VERSION 5.7 ;
  NOWIREEXTENSIONATPIN ON ;
  DIVIDERCHAR "/" ;
  BUSBITCHARS "[]" ;
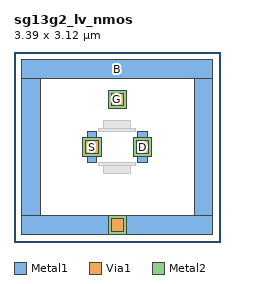
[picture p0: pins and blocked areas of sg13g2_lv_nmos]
MACRO sg13g2_lv_nmos
  CLASS BLOCK ;
  FOREIGN sg13g2_lv_nmos ;
  ORIGIN 1.130 1.310 ;
  SIZE 3.390 BY 3.120 ;
  PIN S
    ANTENNADIFFAREA 0.132500 ;
    PORT
      LAYER Metal1 ;
        RECT 0.070 0.400 0.230 0.500 ;
        RECT 0.000 0.100 0.300 0.400 ;
        RECT 0.070 0.000 0.230 0.100 ;
      LAYER Via1 ;
        RECT 0.050 0.150 0.250 0.350 ;
      LAYER Metal2 ;
        RECT 0.000 0.100 0.300 0.400 ;
    END
  END S
  PIN D
    ANTENNADIFFAREA 0.132500 ;
    PORT
      LAYER Metal1 ;
        RECT 0.900 0.400 1.060 0.500 ;
        RECT 0.830 0.100 1.130 0.400 ;
        RECT 0.900 0.000 1.060 0.100 ;
      LAYER Via1 ;
        RECT 0.880 0.150 1.080 0.350 ;
      LAYER Metal2 ;
        RECT 0.830 0.100 1.130 0.400 ;
    END
  END D
  PIN G
    PORT
      LAYER Metal1 ;
        RECT 0.415 0.880 0.715 1.180 ;
      LAYER Via1 ;
        RECT 0.465 0.930 0.665 1.130 ;
      LAYER Metal2 ;
        RECT 0.415 0.880 0.715 1.180 ;
    END
  END G
  PIN B
    ANTENNADIFFAREA 3.234000 ;
    PORT
      LAYER Metal1 ;
        RECT -1.000 1.380 2.130 1.680 ;
        RECT -1.000 -0.880 -0.700 1.380 ;
        RECT 1.830 -0.880 2.130 1.380 ;
        RECT -1.000 -1.180 2.130 -0.880 ;
      LAYER Via1 ;
        RECT 0.465 -1.130 0.665 -0.930 ;
      LAYER Metal2 ;
        RECT 0.415 -1.180 0.715 -0.880 ;
    END
  END B
  OBS
      LAYER GatPoly ;
        RECT 0.340 0.550 0.790 0.680 ;
        RECT 0.265 0.500 0.865 0.550 ;
        RECT 0.265 -0.050 0.865 0.000 ;
        RECT 0.340 -0.180 0.790 -0.050 ;
  END
END sg13g2_lv_nmos
END LIBRARY

